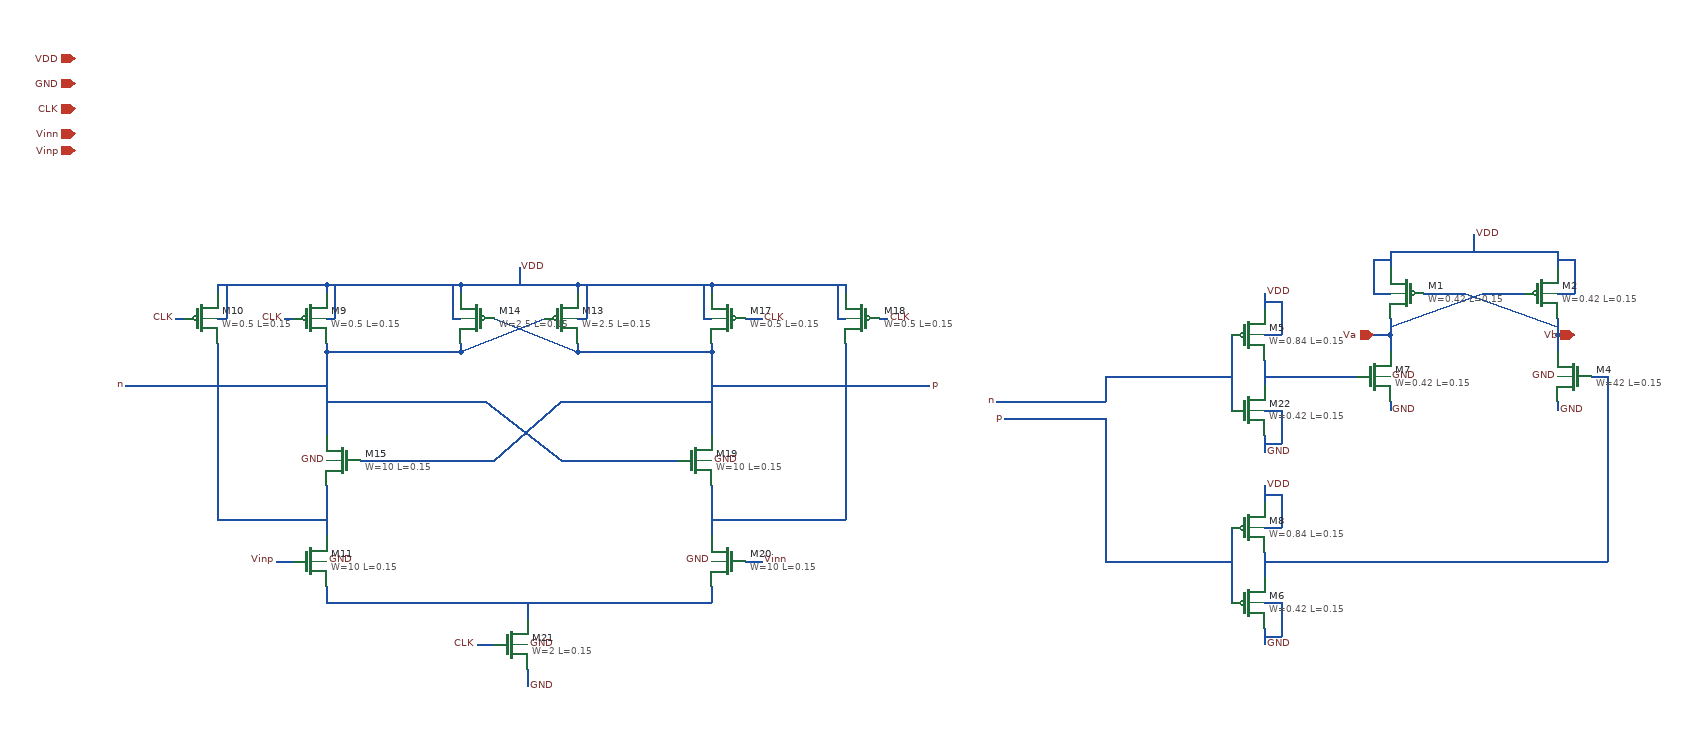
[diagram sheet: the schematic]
v {xschem version=3.4.5 file_version=1.2
}
G {}
K {}
V {}
S {}
E {}
N -20 -60 100 -60 {
lab=n}
N 100 -70 100 -60 {
lab=n}
N -20 -40 100 -40 {
lab=n}
N 100 -40 100 10 {
lab=n}
N 100 -90 130 -90 {
lab=n}
N 100 -90 100 -70 {
lab=n}
N 640 -240 640 -220 {
lab=VDD}
N 640 -190 660 -190 {
lab=VDD}
N 660 -230 660 -190 {
lab=VDD}
N 640 -230 660 -230 {
lab=VDD}
N 440 -240 440 -220 {
lab=VDD}
N 420 -190 440 -190 {
lab=VDD}
N 420 -230 420 -190 {
lab=VDD}
N 420 -230 440 -230 {
lab=VDD}
N 440 -160 440 -140 {
lab=Va}
N 640 -160 640 -140 {
lab=Vb}
N 440 -60 440 -50 {
lab=GND}
N 640 -60 640 -50 {
lab=GND}
N 290 -110 290 -80 {
lab=#net1}
N 250 -140 250 -50 {
lab=n}
N 290 -190 290 -170 {
lab=VDD}
N 290 -20 290 0 {
lab=GND}
N 290 -50 310 -50 {
lab=GND}
N 310 -50 310 -10 {
lab=GND}
N 290 -10 310 -10 {
lab=GND}
N 290 -140 310 -140 {
lab=VDD}
N 310 -180 310 -140 {
lab=VDD}
N 290 -180 310 -180 {
lab=VDD}
N 130 -90 160 -90 {
lab=n}
N 290 120 290 150 {
lab=#net2}
N 250 90 250 180 {
lab=n}
N 290 40 290 60 {
lab=VDD}
N 290 210 290 230 {
lab=GND}
N 290 180 310 180 {
lab=GND}
N 310 180 310 220 {
lab=GND}
N 290 220 310 220 {
lab=GND}
N 290 90 310 90 {
lab=VDD}
N 310 50 310 90 {
lab=VDD}
N 290 50 310 50 {
lab=VDD}
N 160 -90 250 -90 {
lab=n}
N 290 -90 400 -90 {
lab=#net1}
N 100 130 250 130 {
lab=n}
N -830 -130 -830 -120 {
lab=n}
N -830 -120 -670 -120 {
lab=n}
N -670 -130 -670 -120 {
lab=n}
N -830 -200 -830 -190 {
lab=VDD}
N -830 -200 -670 -200 {
lab=VDD}
N -670 -200 -670 -190 {
lab=VDD}
N -830 -120 -830 -20 {
lab=n}
N -530 -130 -530 -120 {
lab=p}
N -530 -120 -370 -120 {
lab=p}
N -370 -130 -370 -120 {
lab=p}
N -530 -200 -530 -190 {
lab=VDD}
N -530 -200 -370 -200 {
lab=VDD}
N -370 -200 -370 -190 {
lab=VDD}
N -370 -120 -370 -20 {
lab=p}
N -790 10 -630 10 {
lab=p}
N -550 -60 -370 -60 {
lab=p}
N -630 10 -550 -60 {
lab=p}
N -550 10 -410 10 {
lab=n}
N -640 -60 -550 10 {
lab=n}
N -830 -60 -640 -60 {
lab=n}
N -670 -120 -570 -160 {
lab=n}
N -630 -160 -530 -120 {
lab=p}
N -830 40 -830 100 {
lab=n}
N -370 40 -370 100 {
lab=#net3}
N -830 160 -830 180 {
lab=#net4}
N -830 180 -370 180 {
lab=#net4}
N -370 160 -370 180 {
lab=#net4}
N -590 180 -590 200 {
lab=#net4}
N -590 260 -590 280 {
lab=GND}
N -670 -200 -530 -200 {
lab=VDD}
N -600 -220 -600 -200 {
lab=VDD}
N -890 130 -870 130 {
lab=Vinp}
N -330 130 -310 130 {
lab=Vinn}
N -330 -160 -310 -160 {
lab=CLK}
N -650 230 -630 230 {
lab=CLK}
N -840 -80 -830 -80 {
lab=n}
N -370 -80 -360 -80 {
lab=p}
N -880 -160 -870 -160 {
lab=CLK}
N -960 -200 -960 -190 {
lab=VDD}
N -960 -200 -830 -200 {
lab=VDD}
N -960 -130 -960 80 {
lab=n}
N -960 80 -830 80 {
lab=n}
N -1010 -160 -1000 -160 {
lab=CLK}
N -210 -200 -210 -190 {
lab=VDD}
N -370 -200 -210 -200 {
lab=VDD}
N -210 -130 -210 80 {
lab=#net3}
N -370 80 -210 80 {
lab=#net3}
N -170 -160 -160 -160 {
lab=CLK}
N -1060 -80 -840 -80 {
lab=n}
N -360 -80 -110 -80 {
lab=p}
N -960 -160 -950 -160 {
lab=VDD}
N -950 -200 -950 -160 {
lab=VDD}
N -830 -160 -820 -160 {
lab=VDD}
N -820 -200 -820 -160 {
lab=VDD}
N -680 -160 -670 -160 {
lab=VDD}
N -680 -200 -680 -160 {
lab=VDD}
N -530 -160 -520 -160 {
lab=VDD}
N -520 -200 -520 -160 {
lab=VDD}
N -380 -160 -370 -160 {
lab=VDD}
N -380 -200 -380 -160 {
lab=VDD}
N -220 -160 -210 -160 {
lab=VDD}
N -220 -200 -220 -160 {
lab=VDD}
N -30 -60 -20 -60 {
lab=n}
N -1070 -80 -1060 -80 {
lab=n}
N 100 10 100 130 {
lab=n}
N 440 -140 440 -120 {
lab=Va}
N 680 -90 700 -90 {
lab=#net2}
N 700 -90 700 130 {
lab=#net2}
N 290 130 700 130 {
lab=#net2}
N 640 -140 640 -120 {
lab=Vb}
N 440 -240 640 -240 {
lab=VDD}
N 540 -260 540 -240 {
lab=VDD}
N 420 -140 440 -140 {
lab=Va}
N 640 -140 660 -140 {
lab=Vb}
N 480 -190 530 -190 {
lab=Vb}
N 530 -190 640 -150 {
lab=Vb}
N 550 -190 600 -190 {
lab=Va}
N 440 -150 550 -190 {
lab=Va}
C {devices/ipin.sym} -1130 -470 0 0 {name=p17 lab=VDD}
C {devices/ipin.sym} -1130 -440 0 0 {name=p18 lab=GND
}
C {devices/ipin.sym} -1130 -410 0 0 {name=p21 lab=CLK
}
C {sky130_fd_pr/nfet_01v8.sym} 660 -90 0 1 {name=M4
L=0.15
W=42
nf=1 
mult=1
ad="'int((nf+1)/2) * W/nf * 0.29'" 
pd="'2*int((nf+1)/2) * (W/nf + 0.29)'"
as="'int((nf+2)/2) * W/nf * 0.29'" 
ps="'2*int((nf+2)/2) * (W/nf + 0.29)'"
nrd="'0.29 / W'" nrs="'0.29 / W'"
sa=0 sb=0 sd=0
model=nfet_01v8
spiceprefix=X
}
C {devices/lab_pin.sym} 440 -90 0 1 {name=p8 sig_type=std_logic lab=GND
}
C {devices/lab_pin.sym} 640 -90 0 0 {name=p9 sig_type=std_logic lab=GND
}
C {devices/lab_pin.sym} 540 -260 0 1 {name=p11 sig_type=std_logic lab=VDD}
C {devices/lab_pin.sym} 440 -50 0 1 {name=p12 sig_type=std_logic lab=GND
}
C {devices/lab_pin.sym} 640 -50 0 1 {name=p13 sig_type=std_logic lab=GND
}
C {devices/ipin.sym} -1130 -380 0 0 {name=p5 lab=Vinn
}
C {devices/ipin.sym} -1130 -360 0 0 {name=p14 lab=Vinp
}
C {devices/opin.sym} 660 -140 2 1 {name=p19 lab=Vb}
C {devices/opin.sym} 420 -140 0 1 {name=p20 lab=Va}
C {sky130_fd_pr/pfet_01v8.sym} 270 -140 0 0 {name=M5
L=0.15
W=0.84
nf=1
mult=1
ad="'int((nf+1)/2) * W/nf * 0.29'" 
pd="'2*int((nf+1)/2) * (W/nf + 0.29)'"
as="'int((nf+2)/2) * W/nf * 0.29'" 
ps="'2*int((nf+2)/2) * (W/nf + 0.29)'"
nrd="'0.29 / W'" nrs="'0.29 / W'"
sa=0 sb=0 sd=0
model=pfet_01v8
spiceprefix=X
}
C {devices/lab_pin.sym} 290 0 0 1 {name=p22 sig_type=std_logic lab=GND
}
C {devices/lab_pin.sym} 290 -190 0 1 {name=p23 sig_type=std_logic lab=VDD}
C {devices/lab_pin.sym} 290 230 0 1 {name=p1 sig_type=std_logic lab=GND
}
C {devices/lab_pin.sym} 290 40 0 1 {name=p2 sig_type=std_logic lab=VDD}
C {devices/lab_pin.sym} -600 -220 0 1 {name=p4 sig_type=std_logic lab=VDD}
C {devices/lab_pin.sym} -590 280 0 1 {name=p15 sig_type=std_logic lab=GND
}
C {devices/lab_pin.sym} -830 10 0 0 {name=p16 sig_type=std_logic lab=GND
}
C {devices/lab_pin.sym} -370 130 0 0 {name=p24 sig_type=std_logic lab=GND
}
C {devices/lab_pin.sym} -830 130 0 1 {name=p25 sig_type=std_logic lab=GND
}
C {devices/lab_pin.sym} -370 10 0 1 {name=p26 sig_type=std_logic lab=GND
}
C {devices/lab_pin.sym} -310 -160 0 1 {name=p27 sig_type=std_logic lab=CLK}
C {devices/lab_pin.sym} -880 -160 0 0 {name=p28 sig_type=std_logic lab=CLK}
C {devices/lab_pin.sym} -650 230 0 0 {name=p29 sig_type=std_logic lab=CLK}
C {devices/lab_pin.sym} -1010 -160 0 0 {name=p32 sig_type=std_logic lab=CLK}
C {devices/lab_pin.sym} -160 -160 0 1 {name=p33 sig_type=std_logic lab=CLK}
C {devices/lab_pin.sym} -590 230 0 1 {name=p34 sig_type=std_logic lab=GND
}
C {sky130_fd_pr/pfet_01v8.sym} -980 -160 0 0 {name=M10
L=0.15
W=0.5
nf=1
mult=1
ad="'int((nf+1)/2) * W/nf * 0.29'" 
pd="'2*int((nf+1)/2) * (W/nf + 0.29)'"
as="'int((nf+2)/2) * W/nf * 0.29'" 
ps="'2*int((nf+2)/2) * (W/nf + 0.29)'"
nrd="'0.29 / W'" nrs="'0.29 / W'"
sa=0 sb=0 sd=0
model=pfet_01v8
spiceprefix=X
}
C {sky130_fd_pr/pfet_01v8.sym} -850 -160 0 0 {name=M9
L=0.15
W=0.5
nf=1
mult=1
ad="'int((nf+1)/2) * W/nf * 0.29'" 
pd="'2*int((nf+1)/2) * (W/nf + 0.29)'"
as="'int((nf+2)/2) * W/nf * 0.29'" 
ps="'2*int((nf+2)/2) * (W/nf + 0.29)'"
nrd="'0.29 / W'" nrs="'0.29 / W'"
sa=0 sb=0 sd=0
model=pfet_01v8
spiceprefix=X
}
C {sky130_fd_pr/nfet_01v8.sym} -850 130 0 0 {name=M11
L=0.15
W=10
nf=1 
mult=1
ad="'int((nf+1)/2) * W/nf * 0.29'" 
pd="'2*int((nf+1)/2) * (W/nf + 0.29)'"
as="'int((nf+2)/2) * W/nf * 0.29'" 
ps="'2*int((nf+2)/2) * (W/nf + 0.29)'"
nrd="'0.29 / W'" nrs="'0.29 / W'"
sa=0 sb=0 sd=0
model=nfet_01v8
spiceprefix=X
}
C {sky130_fd_pr/pfet_01v8.sym} -550 -160 0 0 {name=M13
L=0.15
W=2.5
nf=1
mult=1
ad="'int((nf+1)/2) * W/nf * 0.29'" 
pd="'2*int((nf+1)/2) * (W/nf + 0.29)'"
as="'int((nf+2)/2) * W/nf * 0.29'" 
ps="'2*int((nf+2)/2) * (W/nf + 0.29)'"
nrd="'0.29 / W'" nrs="'0.29 / W'"
sa=0 sb=0 sd=0
model=pfet_01v8
spiceprefix=X
}
C {sky130_fd_pr/pfet_01v8.sym} -650 -160 0 1 {name=M14
L=0.15
W=2.5
nf=1
mult=1
ad="'int((nf+1)/2) * W/nf * 0.29'" 
pd="'2*int((nf+1)/2) * (W/nf + 0.29)'"
as="'int((nf+2)/2) * W/nf * 0.29'" 
ps="'2*int((nf+2)/2) * (W/nf + 0.29)'"
nrd="'0.29 / W'" nrs="'0.29 / W'"
sa=0 sb=0 sd=0
model=pfet_01v8
spiceprefix=X
}
C {sky130_fd_pr/nfet_01v8.sym} -810 10 0 1 {name=M15
L=0.15
W=10
nf=1 
mult=1
ad="'int((nf+1)/2) * W/nf * 0.29'" 
pd="'2*int((nf+1)/2) * (W/nf + 0.29)'"
as="'int((nf+2)/2) * W/nf * 0.29'" 
ps="'2*int((nf+2)/2) * (W/nf + 0.29)'"
nrd="'0.29 / W'" nrs="'0.29 / W'"
sa=0 sb=0 sd=0
model=nfet_01v8
spiceprefix=X
}
C {sky130_fd_pr/pfet_01v8.sym} -350 -160 0 1 {name=M17
L=0.15
W=0.5
nf=1
mult=1
ad="'int((nf+1)/2) * W/nf * 0.29'" 
pd="'2*int((nf+1)/2) * (W/nf + 0.29)'"
as="'int((nf+2)/2) * W/nf * 0.29'" 
ps="'2*int((nf+2)/2) * (W/nf + 0.29)'"
nrd="'0.29 / W'" nrs="'0.29 / W'"
sa=0 sb=0 sd=0
model=pfet_01v8
spiceprefix=X
}
C {sky130_fd_pr/pfet_01v8.sym} -190 -160 0 1 {name=M18
L=0.15
W=0.5
nf=1
mult=1
ad="'int((nf+1)/2) * W/nf * 0.29'" 
pd="'2*int((nf+1)/2) * (W/nf + 0.29)'"
as="'int((nf+2)/2) * W/nf * 0.29'" 
ps="'2*int((nf+2)/2) * (W/nf + 0.29)'"
nrd="'0.29 / W'" nrs="'0.29 / W'"
sa=0 sb=0 sd=0
model=pfet_01v8
spiceprefix=X
}
C {sky130_fd_pr/nfet_01v8.sym} -390 10 0 0 {name=M19
L=0.15
W=10
nf=1 
mult=1
ad="'int((nf+1)/2) * W/nf * 0.29'" 
pd="'2*int((nf+1)/2) * (W/nf + 0.29)'"
as="'int((nf+2)/2) * W/nf * 0.29'" 
ps="'2*int((nf+2)/2) * (W/nf + 0.29)'"
nrd="'0.29 / W'" nrs="'0.29 / W'"
sa=0 sb=0 sd=0
model=nfet_01v8
spiceprefix=X
}
C {sky130_fd_pr/nfet_01v8.sym} -350 130 0 1 {name=M20
L=0.15
W=10
nf=1 
mult=1
ad="'int((nf+1)/2) * W/nf * 0.29'" 
pd="'2*int((nf+1)/2) * (W/nf + 0.29)'"
as="'int((nf+2)/2) * W/nf * 0.29'" 
ps="'2*int((nf+2)/2) * (W/nf + 0.29)'"
nrd="'0.29 / W'" nrs="'0.29 / W'"
sa=0 sb=0 sd=0
model=nfet_01v8
spiceprefix=X
}
C {sky130_fd_pr/nfet_01v8.sym} -610 230 0 0 {name=M21
L=0.15
W=2
nf=1 
mult=1
ad="'int((nf+1)/2) * W/nf * 0.29'" 
pd="'2*int((nf+1)/2) * (W/nf + 0.29)'"
as="'int((nf+2)/2) * W/nf * 0.29'" 
ps="'2*int((nf+2)/2) * (W/nf + 0.29)'"
nrd="'0.29 / W'" nrs="'0.29 / W'"
sa=0 sb=0 sd=0
model=nfet_01v8
spiceprefix=X
}
C {devices/lab_pin.sym} -1070 -80 0 0 {name=p31 sig_type=std_logic lab=n}
C {devices/lab_pin.sym} -20 -40 0 0 {name=p35 sig_type=std_logic lab=p}
C {devices/lab_pin.sym} -110 -80 0 1 {name=p36 sig_type=std_logic lab=p}
C {devices/lab_pin.sym} -30 -60 0 0 {name=p37 sig_type=std_logic lab=n}
C {devices/lab_pin.sym} -890 130 0 0 {name=p3 sig_type=std_logic lab=Vinp}
C {devices/lab_pin.sym} -310 130 0 1 {name=p30 sig_type=std_logic lab=Vinn}
C {sky130_fd_pr/nfet_01v8.sym} 270 -50 0 0 {name=M22
L=0.15
W=0.42
nf=1 
mult=1
ad="'int((nf+1)/2) * W/nf * 0.29'" 
pd="'2*int((nf+1)/2) * (W/nf + 0.29)'"
as="'int((nf+2)/2) * W/nf * 0.29'" 
ps="'2*int((nf+2)/2) * (W/nf + 0.29)'"
nrd="'0.29 / W'" nrs="'0.29 / W'"
sa=0 sb=0 sd=0
model=nfet_01v8
spiceprefix=X
}
C {sky130_fd_pr/pfet_01v8.sym} 270 90 0 0 {name=M8
L=0.15
W=0.84
nf=1
mult=1
ad="'int((nf+1)/2) * W/nf * 0.29'" 
pd="'2*int((nf+1)/2) * (W/nf + 0.29)'"
as="'int((nf+2)/2) * W/nf * 0.29'" 
ps="'2*int((nf+2)/2) * (W/nf + 0.29)'"
nrd="'0.29 / W'" nrs="'0.29 / W'"
sa=0 sb=0 sd=0
model=pfet_01v8
spiceprefix=X
}
C {sky130_fd_pr/pfet_01v8.sym} 270 180 0 0 {name=M6
L=0.15
W=0.42
nf=1
mult=1
ad="'int((nf+1)/2) * W/nf * 0.29'" 
pd="'2*int((nf+1)/2) * (W/nf + 0.29)'"
as="'int((nf+2)/2) * W/nf * 0.29'" 
ps="'2*int((nf+2)/2) * (W/nf + 0.29)'"
nrd="'0.29 / W'" nrs="'0.29 / W'"
sa=0 sb=0 sd=0
model=pfet_01v8
spiceprefix=X
}
C {sky130_fd_pr/pfet_01v8.sym} 620 -190 0 0 {name=M2
L=0.15
W=0.42
nf=1
mult=1
ad="'int((nf+1)/2) * W/nf * 0.29'" 
pd="'2*int((nf+1)/2) * (W/nf + 0.29)'"
as="'int((nf+2)/2) * W/nf * 0.29'" 
ps="'2*int((nf+2)/2) * (W/nf + 0.29)'"
nrd="'0.29 / W'" nrs="'0.29 / W'"
sa=0 sb=0 sd=0
model=pfet_01v8
spiceprefix=X
}
C {sky130_fd_pr/nfet_01v8.sym} 420 -90 0 0 {name=M7
L=0.15
W=0.42
nf=1 
mult=1
ad="'int((nf+1)/2) * W/nf * 0.29'" 
pd="'2*int((nf+1)/2) * (W/nf + 0.29)'"
as="'int((nf+2)/2) * W/nf * 0.29'" 
ps="'2*int((nf+2)/2) * (W/nf + 0.29)'"
nrd="'0.29 / W'" nrs="'0.29 / W'"
sa=0 sb=0 sd=0
model=nfet_01v8
spiceprefix=X
}
C {sky130_fd_pr/pfet_01v8.sym} 460 -190 0 1 {name=M1
L=0.15
W=0.42
nf=1
mult=1
ad="'int((nf+1)/2) * W/nf * 0.29'" 
pd="'2*int((nf+1)/2) * (W/nf + 0.29)'"
as="'int((nf+2)/2) * W/nf * 0.29'" 
ps="'2*int((nf+2)/2) * (W/nf + 0.29)'"
nrd="'0.29 / W'" nrs="'0.29 / W'"
sa=0 sb=0 sd=0
model=pfet_01v8
spiceprefix=X
}
